VERSION 5.7 ;
  NOWIREEXTENSIONATPIN ON ;
  DIVIDERCHAR "/" ;
  BUSBITCHARS "[]" ;
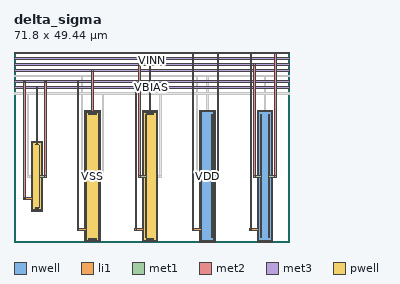
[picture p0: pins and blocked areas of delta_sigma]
MACRO delta_sigma
  CLASS BLOCK ;
  FOREIGN delta_sigma ;
  ORIGIN 4.500 17.095 ;
  SIZE 71.800 BY 49.440 ;
  PIN VDD
    DIRECTION INOUT ;
    USE POWER ;
    ANTENNADIFFAREA 43.781200 ;
    PORT
      LAYER nwell ;
        RECT 43.880 -17.095 47.840 17.095 ;
        RECT 58.840 -17.095 62.800 17.095 ;
      LAYER li1 ;
        RECT 44.060 16.745 47.660 16.915 ;
        RECT 44.060 -13.685 44.230 16.745 ;
        RECT 41.880 -14.185 44.230 -13.685 ;
        RECT 44.060 -16.745 44.230 -14.185 ;
        RECT 46.920 -16.020 47.090 16.020 ;
        RECT 47.490 -16.745 47.660 16.745 ;
        RECT 59.020 16.745 62.620 16.915 ;
        RECT 59.020 -13.685 59.190 16.745 ;
        RECT 56.840 -14.185 59.190 -13.685 ;
        RECT 44.060 -16.915 47.660 -16.745 ;
        RECT 59.020 -16.745 59.190 -14.185 ;
        RECT 61.880 -16.020 62.050 16.020 ;
        RECT 62.450 -16.745 62.620 16.745 ;
        RECT 59.020 -16.915 62.620 -16.745 ;
      LAYER met1 ;
        RECT 46.890 0.200 47.120 16.000 ;
        RECT 61.850 0.200 62.080 16.000 ;
        RECT 46.890 -0.200 48.790 0.200 ;
        RECT 61.850 -0.200 63.750 0.200 ;
        RECT 41.930 -14.135 42.330 -13.735 ;
        RECT 46.890 -16.000 47.120 -0.200 ;
        RECT 56.890 -14.135 57.290 -13.735 ;
        RECT 61.850 -16.000 62.080 -0.200 ;
      LAYER met2 ;
        RECT 41.930 31.895 42.330 32.295 ;
        RECT 48.390 31.895 48.790 32.295 ;
        RECT 56.890 31.895 57.290 32.295 ;
        RECT 63.350 31.895 63.750 32.295 ;
        RECT 41.980 -13.735 42.280 31.895 ;
        RECT 48.440 0.200 48.740 31.895 ;
        RECT 48.390 -0.200 48.790 0.200 ;
        RECT 56.940 -13.735 57.240 31.895 ;
        RECT 63.400 0.200 63.700 31.895 ;
        RECT 63.350 -0.200 63.750 0.200 ;
        RECT 41.930 -14.135 42.330 -13.735 ;
        RECT 56.890 -14.135 57.290 -13.735 ;
      LAYER met3 ;
        RECT -4.500 31.845 67.300 32.345 ;
    END
  END VDD
  PIN VSS
    DIRECTION INOUT ;
    USE GROUND ;
    ANTENNADIFFAREA 36.599998 ;
    PORT
      LAYER pwell ;
        RECT 0.000 -9.050 2.960 9.050 ;
        RECT 13.960 -17.050 17.920 17.050 ;
        RECT 28.920 -17.050 32.880 17.050 ;
      LAYER li1 ;
        RECT 14.140 16.700 17.740 16.870 ;
        RECT 0.180 8.700 2.780 8.870 ;
        RECT 0.180 -5.640 0.350 8.700 ;
        RECT -2.000 -6.140 0.350 -5.640 ;
        RECT 0.180 -8.700 0.350 -6.140 ;
        RECT 2.040 -8.020 2.210 8.020 ;
        RECT 2.610 -8.700 2.780 8.700 ;
        RECT 0.180 -8.870 2.780 -8.700 ;
        RECT 14.140 -13.640 14.310 16.700 ;
        RECT 11.960 -14.140 14.310 -13.640 ;
        RECT 14.140 -16.700 14.310 -14.140 ;
        RECT 17.570 -16.700 17.740 16.700 ;
        RECT 29.100 16.700 32.700 16.870 ;
        RECT 29.100 -13.640 29.270 16.700 ;
        RECT 26.920 -14.140 29.270 -13.640 ;
        RECT 14.140 -16.870 17.740 -16.700 ;
        RECT 29.100 -16.700 29.270 -14.140 ;
        RECT 32.530 -16.700 32.700 16.700 ;
        RECT 29.100 -16.870 32.700 -16.700 ;
      LAYER met1 ;
        RECT 2.010 0.200 2.240 8.000 ;
        RECT 2.010 -0.200 3.910 0.200 ;
        RECT -1.950 -6.090 -1.550 -5.690 ;
        RECT 2.010 -8.000 2.240 -0.200 ;
        RECT 12.010 -14.090 12.410 -13.690 ;
        RECT 26.970 -14.090 27.370 -13.690 ;
      LAYER met2 ;
        RECT -1.950 24.395 -1.550 24.795 ;
        RECT 3.510 24.395 3.910 24.795 ;
        RECT 12.010 24.395 12.410 24.795 ;
        RECT 26.970 24.395 27.370 24.795 ;
        RECT -1.900 -5.690 -1.600 24.395 ;
        RECT 3.560 0.200 3.860 24.395 ;
        RECT 3.510 -0.200 3.910 0.200 ;
        RECT -1.950 -6.090 -1.550 -5.690 ;
        RECT 12.060 -13.690 12.360 24.395 ;
        RECT 27.020 -13.690 27.320 24.395 ;
        RECT 12.010 -14.090 12.410 -13.690 ;
        RECT 26.970 -14.090 27.370 -13.690 ;
      LAYER met3 ;
        RECT -4.500 24.345 67.300 24.845 ;
    END
  END VSS
  PIN VINP
    DIRECTION INPUT ;
    USE SIGNAL ;
    ANTENNAGATEAREA 64.000000 ;
    PORT
      LAYER li1 ;
        RECT 14.940 16.190 16.940 16.360 ;
        RECT 14.940 -16.360 16.940 -16.190 ;
      LAYER met1 ;
        RECT 15.740 16.390 16.140 16.725 ;
        RECT 14.960 16.160 16.920 16.390 ;
        RECT 14.960 -16.390 16.920 -16.160 ;
        RECT 15.740 -16.725 16.140 -16.390 ;
      LAYER met2 ;
        RECT 15.740 27.395 16.140 27.795 ;
        RECT 15.790 16.675 16.090 27.395 ;
        RECT 15.740 16.275 16.140 16.675 ;
      LAYER met3 ;
        RECT -4.500 27.345 67.300 27.845 ;
    END
  END VINP
  PIN VINN
    DIRECTION INPUT ;
    USE SIGNAL ;
    ANTENNAGATEAREA 64.000000 ;
    PORT
      LAYER li1 ;
        RECT 29.900 16.190 31.900 16.360 ;
        RECT 29.900 -16.360 31.900 -16.190 ;
      LAYER met1 ;
        RECT 30.700 16.390 31.100 16.725 ;
        RECT 29.920 16.160 31.880 16.390 ;
        RECT 29.920 -16.390 31.880 -16.160 ;
        RECT 30.700 -16.725 31.100 -16.390 ;
      LAYER met2 ;
        RECT 30.700 30.395 31.100 30.795 ;
        RECT 30.750 16.675 31.050 30.395 ;
        RECT 30.700 16.275 31.100 16.675 ;
      LAYER met3 ;
        RECT -4.500 30.345 67.300 30.845 ;
    END
  END VINN
  PIN VOUTA
    DIRECTION OUTPUT ;
    USE SIGNAL ;
    ANTENNADIFFAREA 18.559999 ;
    PORT
      LAYER li1 ;
        RECT 29.670 -16.020 29.840 16.020 ;
        RECT 59.590 -16.020 59.760 16.020 ;
      LAYER met1 ;
        RECT 29.640 0.200 29.870 16.000 ;
        RECT 59.560 0.200 59.790 16.000 ;
        RECT 27.970 -0.200 29.870 0.200 ;
        RECT 57.890 -0.200 59.790 0.200 ;
        RECT 29.640 -16.000 29.870 -0.200 ;
        RECT 59.560 -16.000 59.790 -0.200 ;
      LAYER met2 ;
        RECT 27.970 28.895 28.370 29.295 ;
        RECT 57.890 28.895 58.290 29.295 ;
        RECT 28.020 0.200 28.320 28.895 ;
        RECT 57.940 0.200 58.240 28.895 ;
        RECT 27.970 -0.200 28.370 0.200 ;
        RECT 57.890 -0.200 58.290 0.200 ;
      LAYER met3 ;
        RECT -4.500 28.845 67.300 29.345 ;
    END
  END VOUTA
  PIN VBIAS
    DIRECTION INPUT ;
    USE SIGNAL ;
    ANTENNAGATEAREA 16.000000 ;
    PORT
      LAYER li1 ;
        RECT 0.980 8.190 1.980 8.360 ;
        RECT 0.980 -8.360 1.980 -8.190 ;
      LAYER met1 ;
        RECT 1.280 8.390 1.680 8.725 ;
        RECT 1.000 8.160 1.960 8.390 ;
        RECT 1.000 -8.390 1.960 -8.160 ;
        RECT 1.280 -8.725 1.680 -8.390 ;
      LAYER met2 ;
        RECT 1.280 22.895 1.680 23.295 ;
        RECT 1.330 8.675 1.630 22.895 ;
        RECT 1.280 8.275 1.680 8.675 ;
      LAYER met3 ;
        RECT -4.500 22.845 67.300 23.345 ;
    END
  END VBIAS
  OBS
      LAYER li1 ;
        RECT 44.860 16.235 46.860 16.405 ;
        RECT 59.820 16.235 61.820 16.405 ;
        RECT 0.750 -8.020 0.920 8.020 ;
        RECT 14.710 -16.020 14.880 16.020 ;
        RECT 17.000 -16.020 17.170 16.020 ;
        RECT 31.960 -16.020 32.130 16.020 ;
        RECT 44.630 -16.020 44.800 16.020 ;
        RECT 44.860 -16.405 46.860 -16.235 ;
        RECT 59.820 -16.405 61.820 -16.235 ;
      LAYER met1 ;
        RECT 45.660 16.435 46.060 16.770 ;
        RECT 60.620 16.435 61.020 16.770 ;
        RECT 44.880 16.205 46.840 16.435 ;
        RECT 59.840 16.205 61.800 16.435 ;
        RECT 0.720 0.200 0.950 8.000 ;
        RECT 14.680 0.200 14.910 16.000 ;
        RECT -0.950 -0.200 0.950 0.200 ;
        RECT 13.010 -0.200 14.910 0.200 ;
        RECT 0.720 -8.000 0.950 -0.200 ;
        RECT 14.680 -16.000 14.910 -0.200 ;
        RECT 16.970 0.200 17.200 16.000 ;
        RECT 31.930 0.200 32.160 16.000 ;
        RECT 44.600 0.200 44.830 16.000 ;
        RECT 16.970 -0.200 18.870 0.200 ;
        RECT 31.930 -0.200 33.830 0.200 ;
        RECT 42.930 -0.200 44.830 0.200 ;
        RECT 16.970 -16.000 17.200 -0.200 ;
        RECT 31.930 -16.000 32.160 -0.200 ;
        RECT 44.600 -16.000 44.830 -0.200 ;
        RECT 44.880 -16.435 46.840 -16.205 ;
        RECT 59.840 -16.435 61.800 -16.205 ;
        RECT 45.660 -16.770 46.060 -16.435 ;
        RECT 60.620 -16.770 61.020 -16.435 ;
      LAYER met2 ;
        RECT 13.010 25.895 13.410 26.295 ;
        RECT 42.930 25.895 43.330 26.295 ;
        RECT 45.660 25.895 46.060 26.295 ;
        RECT 60.620 25.895 61.020 26.295 ;
        RECT -0.950 21.395 -0.550 21.795 ;
        RECT -0.900 0.200 -0.600 21.395 ;
        RECT 13.060 0.200 13.360 25.895 ;
        RECT 18.470 21.395 18.870 21.795 ;
        RECT 33.430 21.395 33.830 21.795 ;
        RECT 18.520 0.200 18.820 21.395 ;
        RECT 33.480 0.200 33.780 21.395 ;
        RECT 42.980 0.200 43.280 25.895 ;
        RECT 45.710 16.720 46.010 25.895 ;
        RECT 60.670 16.720 60.970 25.895 ;
        RECT 45.660 16.320 46.060 16.720 ;
        RECT 60.620 16.320 61.020 16.720 ;
        RECT -0.950 -0.200 -0.550 0.200 ;
        RECT 13.010 -0.200 13.410 0.200 ;
        RECT 18.470 -0.200 18.870 0.200 ;
        RECT 33.430 -0.200 33.830 0.200 ;
        RECT 42.930 -0.200 43.330 0.200 ;
      LAYER met3 ;
        RECT -4.500 25.845 67.300 26.345 ;
        RECT -4.500 21.345 67.300 21.845 ;
  END
END delta_sigma
END LIBRARY

